One B-rep face of a CAD part: STEP entity #776.
In plain terms, the planar face has unit normal (1, 0, 0).
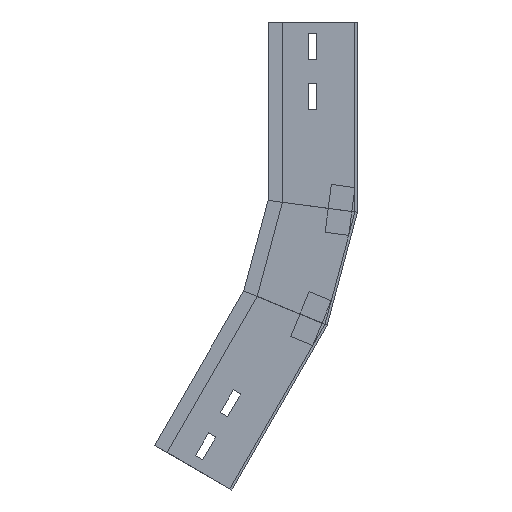
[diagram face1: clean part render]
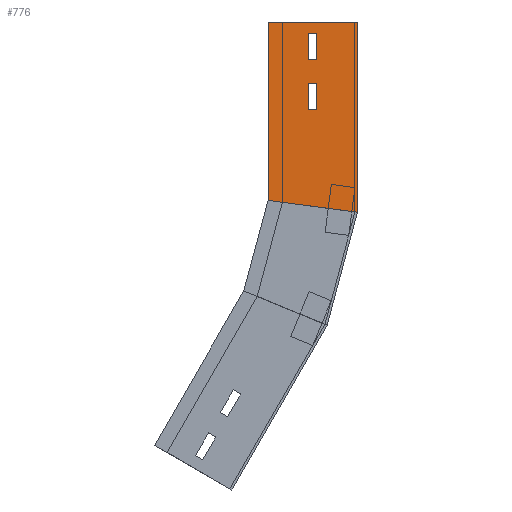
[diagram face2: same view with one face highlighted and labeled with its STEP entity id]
Its self-contained STEP definition (entity closure, numbers rounded to 3 decimals):
#2 = VERTEX_POINT ( 'NONE', #1354 ) ;
#6 = ORIENTED_EDGE ( 'NONE', *, *, #692, .F. ) ;
#11 = ORIENTED_EDGE ( 'NONE', *, *, #31, .F. ) ;
#16 = CARTESIAN_POINT ( 'NONE',  ( 0., 115.046, -327.85 ) ) ;
#31 = EDGE_CURVE ( 'NONE', #1192, #676, #1231, .T. ) ;
#51 = EDGE_CURVE ( 'NONE', #801, #393, #1123, .T. ) ;
#72 = DIRECTION ( 'NONE',  ( 0., -0.866, -0.5 ) ) ;
#76 = CARTESIAN_POINT ( 'NONE',  ( 0., 95.331, -225.702 ) ) ;
#79 = LINE ( 'NONE', #537, #1154 ) ;
#85 = ORIENTED_EDGE ( 'NONE', *, *, #124, .T. ) ;
#95 = CARTESIAN_POINT ( 'NONE',  ( 0., 25.442, -254.651 ) ) ;
#102 = CARTESIAN_POINT ( 'NONE',  ( 0., 37.296, -249.74 ) ) ;
#112 = VERTEX_POINT ( 'NONE', #16 ) ;
#115 = VECTOR ( 'NONE', #590, 1000. ) ;
#124 = EDGE_CURVE ( 'NONE', #801, #602, #230, .T. ) ;
#127 = LINE ( 'NONE', #1393, #1370 ) ;
#132 = EDGE_CURVE ( 'NONE', #795, #1195, #454, .T. ) ;
#176 = CARTESIAN_POINT ( 'NONE',  ( 0., 90.394, -217.151 ) ) ;
#192 = CARTESIAN_POINT ( 'NONE',  ( 0., 104.046, -308.798 ) ) ;
#204 = DIRECTION ( 'NONE',  ( 0., 0., 1. ) ) ;
#212 = PLANE ( 'NONE',  #1155 ) ;
#230 = LINE ( 'NONE', #102, #1181 ) ;
#234 = VECTOR ( 'NONE', #1474, 1000. ) ;
#244 = CARTESIAN_POINT ( 'NONE',  ( 0., 115.046, -327.85 ) ) ;
#261 = EDGE_CURVE ( 'NONE', #112, #1192, #127, .T. ) ;
#265 = ORIENTED_EDGE ( 'NONE', *, *, #876, .T. ) ;
#269 = EDGE_CURVE ( 'NONE', #597, #1388, #1425, .T. ) ;
#296 = CARTESIAN_POINT ( 'NONE',  ( 0., 170.244, -355.455 ) ) ;
#300 = CARTESIAN_POINT ( 'NONE',  ( 0., 129.819, -367.437 ) ) ;
#329 = VECTOR ( 'NONE', #992, 1000. ) ;
#332 = CARTESIAN_POINT ( 'NONE',  ( 0., 105.292, -392.955 ) ) ;
#348 = DIRECTION ( 'NONE',  ( 0., -0.5, 0.866 ) ) ;
#351 = VECTOR ( 'NONE', #430, 1000. ) ;
#388 = ORIENTED_EDGE ( 'NONE', *, *, #132, .F. ) ;
#393 = VERTEX_POINT ( 'NONE', #296 ) ;
#416 = LINE ( 'NONE', #300, #329 ) ;
#430 = DIRECTION ( 'NONE',  ( 0., 0.5, -0.866 ) ) ;
#454 = LINE ( 'NONE', #1132, #520 ) ;
#467 = CARTESIAN_POINT ( 'NONE',  ( 0., 105.292, -392.955 ) ) ;
#479 = CARTESIAN_POINT ( 'NONE',  ( 0., 97.984, -312.298 ) ) ;
#497 = ORIENTED_EDGE ( 'NONE', *, *, #756, .T. ) ;
#520 = VECTOR ( 'NONE', #553, 1000. ) ;
#526 = FACE_OUTER_BOUND ( 'NONE', #584, .T. ) ;
#537 = CARTESIAN_POINT ( 'NONE',  ( 0., 108.984, -331.35 ) ) ;
#553 = DIRECTION ( 'NONE',  ( 0., -0.866, -0.5 ) ) ;
#556 = FACE_BOUND ( 'NONE', #1015, .T. ) ;
#561 = CARTESIAN_POINT ( 'NONE',  ( 0., 135.881, -363.937 ) ) ;
#565 = CARTESIAN_POINT ( 'NONE',  ( 0., 129.819, -367.437 ) ) ;
#584 = EDGE_LOOP ( 'NONE', ( #85, #265, #497, #1486 ) ) ;
#590 = DIRECTION ( 'NONE',  ( 0., 0.866, 0.5 ) ) ;
#597 = VERTEX_POINT ( 'NONE', #565 ) ;
#601 = DIRECTION ( 'NONE',  ( 0., 0.866, 0.5 ) ) ;
#602 = VERTEX_POINT ( 'NONE', #95 ) ;
#653 = CARTESIAN_POINT ( 'NONE',  ( 0., 124.881, -344.885 ) ) ;
#660 = EDGE_LOOP ( 'NONE', ( #1167, #1111, #948, #388 ) ) ;
#661 = FACE_BOUND ( 'NONE', #660, .T. ) ;
#676 = VERTEX_POINT ( 'NONE', #479 ) ;
#692 = EDGE_CURVE ( 'NONE', #2, #112, #1285, .T. ) ;
#706 = ORIENTED_EDGE ( 'NONE', *, *, #1280, .F. ) ;
#756 = EDGE_CURVE ( 'NONE', #834, #393, #1044, .T. ) ;
#761 = CARTESIAN_POINT ( 'NONE',  ( 0., 25.442, -254.651 ) ) ;
#776 = ADVANCED_FACE ( 'NONE', ( #661, #556, #526 ), #212, .F. ) ;
#778 = DIRECTION ( 'NONE',  ( -1., 0., 0. ) ) ;
#795 = VERTEX_POINT ( 'NONE', #653 ) ;
#801 = VERTEX_POINT ( 'NONE', #76 ) ;
#805 = EDGE_CURVE ( 'NONE', #1195, #597, #416, .T. ) ;
#814 = DIRECTION ( 'NONE',  ( 0., -0.924, -0.383 ) ) ;
#829 = CARTESIAN_POINT ( 'NONE',  ( 0., 135.881, -363.937 ) ) ;
#832 = EDGE_CURVE ( 'NONE', #1388, #795, #1112, .T. ) ;
#834 = VERTEX_POINT ( 'NONE', #332 ) ;
#860 = VECTOR ( 'NONE', #989, 1000. ) ;
#868 = DIRECTION ( 'NONE',  ( 0., 0.5, -0.866 ) ) ;
#876 = EDGE_CURVE ( 'NONE', #602, #834, #1016, .T. ) ;
#891 = CARTESIAN_POINT ( 'NONE',  ( 0., 25.442, -254.651 ) ) ;
#928 = DIRECTION ( 'NONE',  ( 0., 0.866, 0.5 ) ) ;
#929 = VECTOR ( 'NONE', #928, 1000. ) ;
#948 = ORIENTED_EDGE ( 'NONE', *, *, #805, .F. ) ;
#987 = CARTESIAN_POINT ( 'NONE',  ( 0., 135.881, -363.937 ) ) ;
#989 = DIRECTION ( 'NONE',  ( 0., 0.5, -0.866 ) ) ;
#992 = DIRECTION ( 'NONE',  ( 0., 0.5, -0.866 ) ) ;
#1015 = EDGE_LOOP ( 'NONE', ( #1023, #6, #706, #11 ) ) ;
#1016 = LINE ( 'NONE', #891, #351 ) ;
#1023 = ORIENTED_EDGE ( 'NONE', *, *, #261, .F. ) ;
#1044 = LINE ( 'NONE', #467, #929 ) ;
#1101 = CARTESIAN_POINT ( 'NONE',  ( 0., 118.819, -348.385 ) ) ;
#1111 = ORIENTED_EDGE ( 'NONE', *, *, #269, .F. ) ;
#1112 = LINE ( 'NONE', #987, #234 ) ;
#1123 = LINE ( 'NONE', #176, #860 ) ;
#1126 = VECTOR ( 'NONE', #72, 1000. ) ;
#1132 = CARTESIAN_POINT ( 'NONE',  ( 0., 124.881, -344.885 ) ) ;
#1154 = VECTOR ( 'NONE', #868, 1000. ) ;
#1155 = AXIS2_PLACEMENT_3D ( 'NONE', #761, #778, #204 ) ;
#1167 = ORIENTED_EDGE ( 'NONE', *, *, #832, .F. ) ;
#1181 = VECTOR ( 'NONE', #814, 1000. ) ;
#1192 = VERTEX_POINT ( 'NONE', #1355 ) ;
#1195 = VERTEX_POINT ( 'NONE', #1101 ) ;
#1231 = LINE ( 'NONE', #192, #1126 ) ;
#1280 = EDGE_CURVE ( 'NONE', #676, #2, #79, .T. ) ;
#1285 = LINE ( 'NONE', #244, #115 ) ;
#1354 = CARTESIAN_POINT ( 'NONE',  ( 0., 108.984, -331.35 ) ) ;
#1355 = CARTESIAN_POINT ( 'NONE',  ( 0., 104.046, -308.798 ) ) ;
#1370 = VECTOR ( 'NONE', #348, 1000. ) ;
#1388 = VERTEX_POINT ( 'NONE', #561 ) ;
#1393 = CARTESIAN_POINT ( 'NONE',  ( 0., 115.046, -327.85 ) ) ;
#1397 = VECTOR ( 'NONE', #601, 1000. ) ;
#1425 = LINE ( 'NONE', #829, #1397 ) ;
#1474 = DIRECTION ( 'NONE',  ( 0., -0.5, 0.866 ) ) ;
#1486 = ORIENTED_EDGE ( 'NONE', *, *, #51, .F. ) ;
